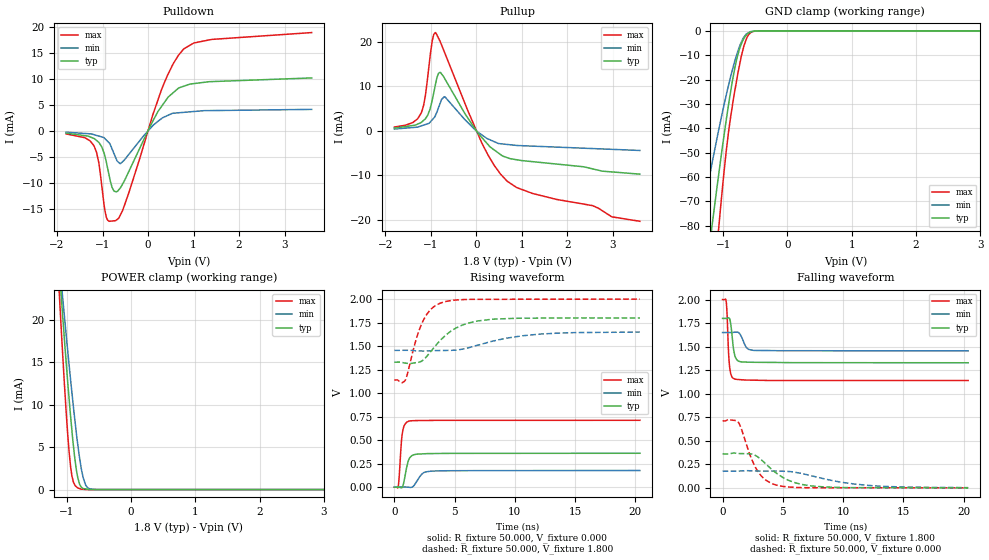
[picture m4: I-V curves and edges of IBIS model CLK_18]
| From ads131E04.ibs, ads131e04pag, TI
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|   CLK 1.8V Model
[Model]   CLK_18
Model_type   I/O
|for ADS1291, ADS1292, ADS1294, ADS1296, and ADS1298 products
|Signals   CLK
Vinl = 0.36
Vinh = 1.44
Vmeas = 0.9
Vref = 0.9
Cref = 2pF
Rref = 50
|   typ   min   max
|   (nom PVT)   (Fast PVT)   (slow PVT)
|C_comp from frequency sweep method (F=64MHz)
|   (HIGH Z)
|C_comp   3.3925780e-12   2.5074750e-12   4.1770800e-12
|   (ON state)
|C_comp   6.2108590e-12   5.2318900e-12   6.1945700e-12
|   (OFF state)
|C_comp   5.5891630e-12   4.8298730e-12   6.3388710e-12
|C_comp from LC tank measurement(L=1nH)
|   (HIGH Z)
|C_comp   2.680E-12   2.023E-12   3.327E-12
|   (ON state)
C_comp   2.729E-12   2.099E-12   3.405E-12
|   (OFF state)
|C_comp   2.780E-12   2.129E-12   3.420E-12
| Where   nom PVT is  Nominal Process, 1.8V, 27C
|   Fast PVT is Strong Process, 2V, -40C
|   Slow PVT is Weak Process, 1.65V, 85C
[Voltage Range]   1.8   1.65   2
[Temperature Range]   27   85   -40
[Pullup Reference]   1.8   1.65   2
[Pulldown Reference]   0   0   0
[Power Clamp Reference]   1.8   1.65   2
[GND Clamp Reference]   0   0   0
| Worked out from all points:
|   slope of the pulldown table from 0 to 0.27 V, typ, clamps not added: 62.3 ohm
|   slope of the pullup table from 0 to 0.27 V, typ, clamps not added: 82.7 ohm
|   GND clamp passes 1 mA (typ) near -0.61 V on its own axis
|   POWER clamp passes 1 mA (typ) near -0.81 V on its own axis
|   falling waveform, R_fixture 50.000, V_fixture 1.800: 20-80 % time 269ps typ, 419ps min, 188ps max; typ from 1.8 V to 1.33 V
|   rising waveform, R_fixture 50.000, V_fixture 0.000: 20-80 % time 368ps typ, 577ps min, 242ps max; typ from 0 V to 0.361 V
|   rising waveform, R_fixture 50.000, V_fixture 1.800: 20-80 % time 2.43ns typ, 4.23ns min, 1.35ns max; typ from 1.33 V to 1.8 V
|   falling waveform, R_fixture 50.000, V_fixture 0.000: 20-80 % time 2.34ns typ, 4.25ns min, 1.4ns max; typ from 0.361 V to 0 V
[Pulldown]
|   Voltage   I(typ)   I(min)   I(max)
-1.8V     -493.2uA   -302.1uA   -631.4uA
-1.191V   -1.505mA   -775.3uA   -2.881mA
-1.084V   -2.234mA   -1.045mA   -6.051mA
-918.3mV  -5.961mA   -1.79mA    -16.6mA
-791.5mV  -10.9mA    -3.51mA    -17.41mA
-714.1mV  -11.75mA   -5.143mA   -17.34mA
-599.3mV  -10.92mA   -6.311mA   -16.09mA
311.8mV   4.85mA     2.433mA    8.245mA
556.7mV   7.331mA    3.351mA    12.94mA
782.1mV   8.544mA    3.517mA    15.72mA
1.395V    9.438mA    3.859mA    17.56mA
3.595V    10.14mA    4.088mA    18.88mA
[GND Clamp]
|   Voltage   I(typ)   I(min)   I(max)
-1.8V     -221.5mA   -150.4mA   -312.9mA
-1.346V   -117.2mA   -78.92mA   -166mA
-1.171V   -79.66mA   -54.16mA   -111.4mA
-1.071V   -59.22mA   -40.84mA   -81.37mA
-1.048V   -54.64mA   -37.94mA   -74.6mA
-989.5mV  -43.49mA   -30.77mA   -58.64mA
-918.4mV  -30.68mA   -22.58mA   -41.92mA
-825.9mV  -16.25mA   -13.02mA   -25.67mA
-746mV    -7.45mA    -6.512mA   -14.15mA
-674.7mV  -3.047mA   -2.53mA    -5.952mA
-571.9mV  -449.7uA   -310.7uA   -783.2uA
3.595V    0A         0A         0A
[Pullup]
|   Voltage   I(typ)   I(min)   I(max)
-1.8V     604.7uA    404.2uA    846.7uA
-1.396V   1.195mA    743.5uA    1.856mA
-1.209V   1.89mA     1.114mA    4.009mA
-1.121V   2.66mA     1.413mA    7.716mA
-1.019V   4.768mA    1.896mA    16.28mA
-964.3mV  7.072mA    2.522mA    20.37mA
-899.1mV  10.29mA    3.431mA    22.08mA
-796.1mV  13.13mA    6.14mA     20.14mA
-688.4mV  11.64mA    7.634mA    17.4mA
123.9mV   -1.528mA   -935.7uA   -2.78mA
667.9mV   -5.984mA   -3.047mA   -11.2mA
3.595V    -9.731mA   -4.412mA   -20.33mA
[POWER Clamp]
|   Voltage   I(typ)   I(min)   I(max)
-1.8V     105.8mA    89.96mA    127.6mA
-1.113V   25.88mA    26.81mA    22.85mA
-1.076V   21.9mA     23.73mA    17.78mA
-1.062V   20.36mA    22.51mA    15.82mA
-1.009V   15.06mA    18.29mA    9.223mA
-959.2mV  10.4mA     14.44mA    4.184mA
-935.9mV  8.356mA    12.66mA    2.499mA
-896mV    5.198mA    9.77mA     901.6uA
-825.9mV  1.35mA     5.197mA    188.8uA
-743.6mV  126uA      1.39mA     36.03uA
-649.3mV  11.16uA    106.7uA    6.529uA
3.595V    0A         0A         0A
[Ramp]
R_load = 50
|   typ   min   max
dV/dt_r   0.216436/3.65589e-010  0.106791/5.67116e-010  0.426817/2.41454e-010
dV/dt_f   0.282366/2.66854e-010  0.116758/4.12675e-010  0.515704/1.86981e-010
[Falling Waveform]
R_fixture = 50.000
V_fixture = 1.800
V_fixture_min = 1.650
V_fixture_max = 2.000
C_fixture = 0.000
|  time   V(typ)   V(min)   V(max)
0s        1.8V       1.65V      2V
292.9ps   1.8V       1.65V      1.988V
370.7ps   1.802V     1.65V      1.847V
497.6ps   1.806V     1.65V      1.434V
583.4ps   1.796V     1.65V      1.288V
995.4ps   1.416V     1.653V     1.156V
1.306ns   1.347V     1.652V     1.151V
1.996ns   1.336V     1.488V     1.145V
2.58ns    1.334V     1.46V      1.144V
20.38ns   1.329V     1.455V     1.14V
[Rising Waveform]
R_fixture = 50.000
V_fixture = 0.000
V_fixture_min = 0.000
V_fixture_max = 0.000
C_fixture = 0.000
|  time   V(typ)   V(min)   V(max)
0s        -431.4nV   2.268mV    -804.2nV
331.8ps   193.7uV    2.309mV    13.72mV
409ps     -442.6uV   2.318mV    125.3mV
592.7ps   -6.331mV   2.34mV     491mV
719.1ps   18.89mV    2.356mV    612.2mV
1.203ns   294.8mV    -967uV     702.5mV
1.543ns   340.6mV    5.72mV     707mV
2.355ns   354.5mV    147.2mV    709.1mV
3.046ns   357.6mV    170.7mV    710mV
20.38ns   360.7mV    177.2mV    711.4mV
[Rising Waveform]
R_fixture = 50.000
V_fixture = 1.800
V_fixture_min = 1.650
V_fixture_max = 2.000
C_fixture = 0.000
|  time   V(typ)   V(min)   V(max)
0s        1.329V     1.455V     1.14V
897.3ps   1.32V      1.456V     1.135V
1.83ns    1.325V     1.45V      1.581V
2.395ns   1.352V     1.448V     1.772V
3.101ns   1.455V     1.451V     1.9V
4.073ns   1.594V     1.454V     1.969V
5.704ns   1.727V     1.469V     1.995V
8.194ns   1.787V     1.554V     1.998V
12.17ns   1.799V     1.629V     1.999V
20.38ns   1.8V       1.65V      2V
[Falling Waveform]
R_fixture = 50.000
V_fixture = 0.000
V_fixture_min = 0.000
V_fixture_max = 0.000
C_fixture = 0.000
|  time   V(typ)   V(min)   V(max)
0s        360.7mV    177.2mV    711.4mV
1.289ns   365.9mV    177.9mV    699.3mV
2.339ns   360.9mV    181.2mV    328.4mV
2.859ns   334.7mV    178.9mV    188.6mV
3.555ns   258mV      178.5mV    85.25mV
4.436ns   159.2mV    178mV      30.49mV
6.096ns   51.62mV    163.3mV    4.507mV
8.551ns   8.727mV    92.22mV    1.565mV
12.72ns   1.932mV    20.53mV    1.013mV
20.38ns   -431.4nV   2.268mV    -804.2nV
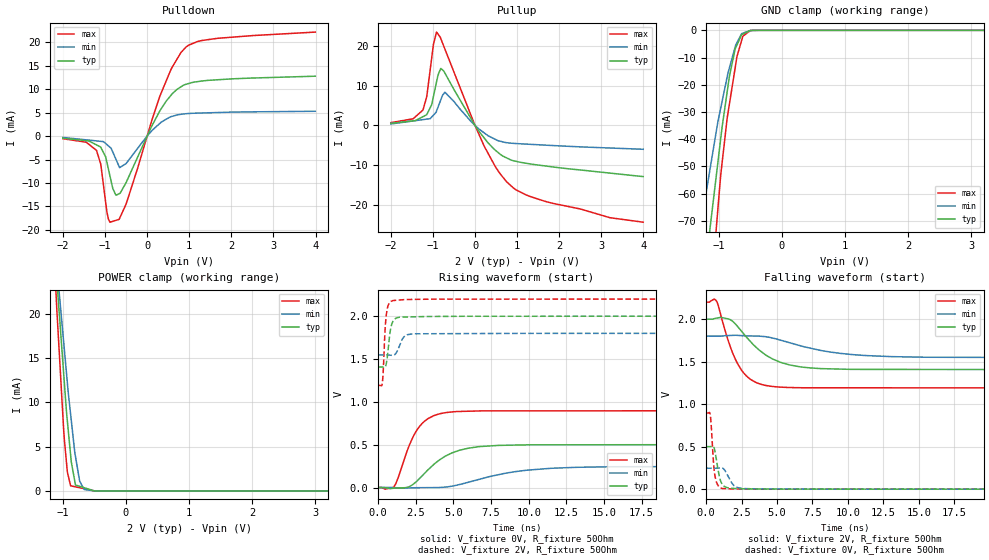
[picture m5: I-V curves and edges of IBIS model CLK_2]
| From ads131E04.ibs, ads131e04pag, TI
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|   CLK 2.0V Model
[Model]   CLK_2
Model_type   I/O
|for ADS1299 products
|Signals   CLK
Vinl = 0.4
Vinh = 1.6
Vmeas = 1.0
Vref = 1.0
Cref = 2pF
Rref = 50
|   typ   min   max
|   (nom PVT)   (Fast PVT)   (slow PVT)
|C_comp from LC tank measurement(L=1nH)
|   (HIGH Z)
|C_comp   2.643E-12   1.996E-12   3.327E-12
|   (ON state)
C_comp   2.680E-12   2.080E-12   3.358E-12
|   (OFF state)
|C_comp   2.720E-12   2.184E-12   3.389E-12
| Where   nom PVT is  Nominal Process, 2V, 27C
|   Fast PVT is Strong Process, 2.2V, -40C
|   Slow PVT is Weak Process, 1.8V, 85C
[Voltage Range]   2   1.8   2.2
[Temperature Range]   27   85   -40
[Pullup Reference]   2   1.8   2.2
[Pulldown Reference]   0   0   0
[Power Clamp Reference]   2   1.8   2.2
[GND Clamp Reference]   0   0   0
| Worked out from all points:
|   slope of the pulldown table from 0 to 0.3 V, typ, clamps not added: 56 ohm
|   slope of the pullup table from 0 to 0.3 V, typ, clamps not added: 70.1 ohm
|   GND clamp passes 1 mA (typ) near -0.58 V on its own axis
|   POWER clamp passes 1 mA (typ) near -0.81 V on its own axis
|   falling waveform, V_fixture 2V, R_fixture 50Ohm: 20-80 % time 2.39ns typ, 4.11ns min, 1.41ns max; typ from 2 V to 1.41 V
|   rising waveform, V_fixture 0V, R_fixture 50Ohm: 20-80 % time 2.14ns typ, 3.9ns min, 1.31ns max; typ from 0 V to 0.501 V
|   rising waveform, V_fixture 2V, R_fixture 50Ohm: 20-80 % time 259ps typ, 388ps min, 183ps max; typ from 1.41 V to 2 V
|   falling waveform, V_fixture 0V, R_fixture 50Ohm: 20-80 % time 342ps typ, 520ps min, 232ps max; typ from 0.501 V to 0 V
[Pulldown]
|   Voltage   I(typ)   I(min)   I(max)
-2V       -446.8uA   -277.7uA   -546.8uA
-1.203V   -1.857mA   -1.015mA   -3.03mA
-1.098V   -2.444mA   -1.112mA   -6.179mA
-920.4mV  -6.972mA   -2.066mA   -17.65mA
-815.9mV  -11.15mA   -3.375mA   -18.18mA
-664.4mV  -12.28mA   -6.492mA   -17.75mA
-499mV    -9.914mA   -5.85mA    -14.5mA
303.4mV   5.413mA    2.729mA    8.536mA
591.2mV   8.984mA    4.218mA    14.65mA
921.7mV   11.06mA    4.783mA    18.99mA
1.667V    12.03mA    5.035mA    20.87mA
3.994V    12.79mA    5.303mA    22.2mA
[GND Clamp]
|   Voltage   I(typ)   I(min)   I(max)
-2V       -269mA     -184.2mA   -378.3mA
-1.285V   -104.2mA   -71.46mA   -146.6mA
-1.134V   -72.01mA   -50.49mA   -100.5mA
-1.098V   -64.89mA   -45.37mA   -89.18mA
-1.016V   -48.91mA   -33.89mA   -66.25mA
-965.6mV  -39.22mA   -28.24mA   -52.59mA
-866.6mV  -22.65mA   -17.13mA   -32.32mA
-830.5mV  -16.83mA   -13.77mA   -27.05mA
-712.4mV  -5.47mA    -4.604mA   -9.832mA
-635.3mV  -1.567mA   -1.183mA   -3.571mA
-452.8mV  -47.95uA   -18.58uA   -21.29uA
3.994V    0A         0A         0A
[Pullup]
|   Voltage   I(typ)   I(min)   I(max)
-2V       546.5uA    370.9uA    725.3uA
-1.473V   1.156mA    1.134mA    1.672mA
-1.239V   2.209mA    1.472mA    3.871mA
-1.145V   2.784mA    1.608mA    7.428mA
-1.03V    5.235mA    2.119mA    16.97mA
-914.3mV  10.99mA    3.649mA    23.59mA
-815.9mV  14.36mA    6.395mA    22.02mA
-715.6mV  13.25mA    8.39mA     19.3mA
212.3mV   -3.088mA   -1.835mA   -5.114mA
752.4mV   -8.207mA   -4.357mA   -14.26mA
1.667V    -10.23mA   -4.968mA   -19.18mA
3.994V    -12.92mA   -6.02mA    -24.44mA
[POWER Clamp]
|   Voltage   I(typ)   I(min)   I(max)
-2V       129.9mA    109.1mA    159.1mA
-1.268V   43.13mA    40.31mA    45.46mA
-1.098V   24.26mA    25.49mA    20.67mA
-1.077V   21.92mA    23.81mA    18.02mA
-978.5mV  12.38mA    16.1mA     5.95mA
-929.4mV  7.886mA    12.23mA    2.13mA
-877.6mV  4.05mA     8.652mA    577.2uA
-800.7mV  668.9uA    3.894mA    460uA
-736.6mV  526.2uA    1.192mA    362.2uA
-663.7mV  363.8uA    165.5uA    251uA
-500.2mV  55.26nA    1.607uA    1.869uA
3.994V    0A         0A         0A
[Ramp]
R_load = 50
|   typ   min   max
dV/dt_r   0.300353/2.13181e-009  0.147667/3.87445e-009  0.537699/1.30968e-009
dV/dt_f   0.356044/2.37906e-009  0.151292/4.09808e-009  0.605232/1.41362e-009
[Falling Waveform]
V_fixture = 2V
V_fixture_min = 1.8V
V_fixture_max = 2.2V
R_fixture = 50Ohm
C_fixture = 0F
|   Time   V(typ)   V(min)   V(max)
0s        2V         1.8V       2.2V
753.9ps   2.013V     1.8V       2.208V
1.711ns   1.993V     1.808V     1.673V
2.468ns   1.864V     1.806V     1.408V
3.126ns   1.737V     1.802V     1.292V
4.015ns   1.602V     1.797V     1.227V
5.887ns   1.461V     1.723V     1.196V
8.107ns   1.418V     1.631V     1.193V
13.07ns   1.409V     1.559V     1.192V
25ns      1.407V     1.548V     1.191V
[Rising Waveform]
V_fixture = 0V
V_fixture_min = 0V
V_fixture_max = 0V
R_fixture = 50Ohm
C_fixture = 0F
|   Time   V(typ)   V(min)   V(max)
0s        183.8nV    7.808uV    2.991nV
1.044ns   -8.034mV   -775.9uV   10.05mV
1.314ns   -4.793mV   -3.416mV   108mV
2.073ns   11.03mV    -4.509mV   495.9mV
2.579ns   75.85mV    -2.162mV   672.2mV
3.281ns   201.5mV    -1.317mV   801.1mV
4.203ns   337.4mV    2.169mV    865.5mV
6.599ns   475mV      90.46mV    893.5mV
11.42ns   498.8mV    223.9mV    895.2mV
25ns      500.6mV    246.1mV    896.2mV
[Rising Waveform]
V_fixture = 2V
V_fixture_min = 1.8V
V_fixture_max = 2.2V
R_fixture = 50Ohm
C_fixture = 0F
|   Time   V(typ)   V(min)   V(max)
0s        1.407V     1.548V     1.191V
280.5ps   1.406V     1.548V     1.229V
342.2ps   1.404V     1.548V     1.385V
465.1ps   1.407V     1.548V     1.865V
581.3ps   1.491V     1.548V     2.068V
794.8ps   1.819V     1.545V     2.165V
985.6ps   1.941V     1.544V     2.183V
1.706ns   1.99V      1.758V     2.193V
2.305ns   1.992V     1.794V     2.196V
25ns      2V         1.8V       2.2V
[Falling Waveform]
|Gnd
V_fixture = 0V
V_fixture_min = 0V
V_fixture_max = 0V
R_fixture = 50Ohm
C_fixture = 0F
|   Time   V(typ)   V(min)   V(max)
0s        500.6mV    246.1mV    896.2mV
293.6ps   500.4mV    246.1mV    873.2mV
361.8ps   502.7mV    246.1mV    743.5mV
533.6ps   497.5mV    246mV      287mV
653.3ps   420.1mV    246mV      130.7mV
920.4ps   158.6mV    249.3mV    27.36mV
1.103ns   67.19mV    250mV      9.48mV
1.968ns   8.479mV    41.8mV     2.924mV
2.739ns   3.643mV    7.088mV    1.938mV
25ns      189.2nV    8.004uV    64.84nV
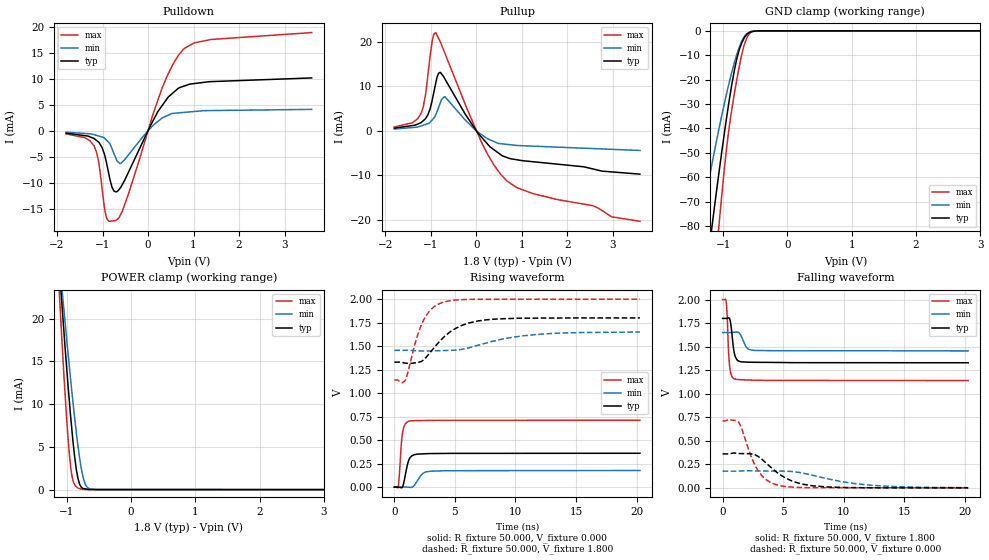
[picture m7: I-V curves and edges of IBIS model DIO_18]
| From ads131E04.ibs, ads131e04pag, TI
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|   DIO 1.8V Model
[Model]   DIO_18
Model_type   I/O
|for ADS1291, ADS1292, ADS1294, ADS1296, and ADS1298 products
|Signals   SCLK, DAISY_IN
Vinl = .36
Vinh = 1.44
Vmeas = 0.9
Vref = 0.9
Cref = 2pF
Rref = 50
|   typ   min   max
|   (nom PVT)   (Fast PVT)   (slow PVT)
|C_comp from frequency sweep method (F=64MHz)
|   (HIGH Z)
|C_comp   3.4090070e-12   2.5132430e-12   4.2130700e-12
|   (ON state)
|C_comp   6.2272870e-12   5.2376580e-12   6.2305600e-12
|   (OFF state)
|C_comp   5.6001660e-12   4.8341510e-12   6.3523670e-12
|C_comp from LC tank measurement(L=1nH)
|   (HIGH Z)
|C_comp   2.692E-12   2.052E-12   3.343E-12
|   (ON state)
C_comp   2.680E-12   2.052E-12   3.343E-12
|   (OFF state)
|C_comp   2.793E-12   2.148E-12   3.318E-12
| Where   nom PVT is  Nominal Process, 1.8V, 27C
|   Fast PVT is Strong Process, 2V, -40C
|   Slow PVT is Weak Process, 1.65V, 85C
[Voltage Range]   1.8   1.65   2
[Temperature Range]   27   85   -40
[Pullup Reference]   1.8   1.65   2
[Pulldown Reference]   0   0   0
[Power Clamp Reference]   1.8   1.65   2
[GND Clamp Reference]   0   0   0
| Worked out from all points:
|   slope of the pulldown table from 0 to 0.27 V, typ, clamps not added: 62.3 ohm
|   slope of the pullup table from 0 to 0.27 V, typ, clamps not added: 82.6 ohm
|   GND clamp passes 1 mA (typ) near -0.61 V on its own axis
|   POWER clamp passes 1 mA (typ) near -0.81 V on its own axis
|   falling waveform, R_fixture 50.000, V_fixture 1.800: 20-80 % time 273ps typ, 421ps min, 190ps max; typ from 1.8 V to 1.33 V
|   rising waveform, R_fixture 50.000, V_fixture 0.000: 20-80 % time 375ps typ, 589ps min, 246ps max; typ from 0 V to 0.361 V
|   rising waveform, R_fixture 50.000, V_fixture 1.800: 20-80 % time 2.44ns typ, 4.26ns min, 1.35ns max; typ from 1.33 V to 1.8 V
|   falling waveform, R_fixture 50.000, V_fixture 0.000: 20-80 % time 2.39ns typ, 4.39ns min, 1.43ns max; typ from 0.361 V to 0 V
[Pulldown]
|   Voltage   I(typ)   I(min)   I(max)
-1.8V     -493.2uA   -302.1uA   -631.4uA
-1.191V   -1.504mA   -776.7uA   -2.888mA
-1.088V   -2.209mA   -1.036mA   -5.858mA
-918.2mV  -5.97mA    -1.787mA   -16.6mA
-791.5mV  -10.9mA    -3.51mA    -17.41mA
-713.9mV  -11.76mA   -5.147mA   -17.34mA
-597.1mV  -10.88mA   -6.302mA   -16.05mA
305mV     4.764mA    2.381mA    8.093mA
548.6mV   7.268mA    3.324mA    12.81mA
785.1mV   8.557mA    3.504mA    15.74mA
1.391V    9.437mA    3.861mA    17.55mA
3.595V    10.14mA    4.088mA    18.88mA
[GND Clamp]
|   Voltage   I(typ)   I(min)   I(max)
-1.8V     -221.5mA   -150.4mA   -312.9mA
-1.345V   -116.9mA   -78.75mA   -165.7mA
-1.173V   -79.95mA   -54.35mA   -111.8mA
-1.066V   -58.37mA   -40.28mA   -80.1mA
-952.5mV  -36.68mA   -26.42mA   -49.43mA
-880.8mV  -24.43mA   -18.46mA   -34.77mA
-818mV    -15.15mA   -12.29mA   -24.49mA
-749.1mV  -7.708mA   -6.74mA    -14.56mA
-638.6mV  -1.69mA    -1.264mA   -3.326mA
-563.3mV  -385.1uA   -280.7uA   -585uA
-450.7mV  -21.72uA   -40.51uA   -19.25uA
3.595V    0A         0A         0A
[Pullup]
|   Voltage   I(typ)   I(min)   I(max)
-1.8V     604.7uA    404.2uA    846.7uA
-1.402V   1.188mA    738.6uA    1.825mA
-1.212V   1.854mA    1.106mA    3.943mA
-1.121V   2.67mA     1.418mA    7.738mA
-1.021V   4.713mA    1.866mA    16.14mA
-964mV    7.077mA    2.51mA     20.38mA
-898.8mV  10.29mA    3.441mA    22.08mA
-796.1mV  13.13mA    6.135mA    20.14mA
-688.4mV  11.64mA    7.634mA    17.4mA
125.5mV   -1.548mA   -927.7uA   -2.813mA
666.9mV   -5.975mA   -3.039mA   -11.2mA
3.595V    -9.731mA   -4.412mA   -20.33mA
[POWER Clamp]
|   Voltage   I(typ)   I(min)   I(max)
-1.8V     105.8mA    89.96mA    127.6mA
-1.113V   25.84mA    26.78mA    22.81mA
-1.075V   21.71mA    23.58mA    17.54mA
-1.061V   20.35mA    22.5mA     15.8mA
-1.009V   15.02mA    18.26mA    9.187mA
-959mV    10.37mA    14.42mA    4.163mA
-935.7mV  8.337mA    12.64mA    2.485mA
-895.7mV  5.18mA     9.749mA    895.8uA
-825.5mV  1.34mA     5.18mA     187.3uA
-741.4mV  123.4uA    1.327mA    34.5uA
-653.5mV  16.35uA    121.6uA    6.493uA
3.595V    0A         0A         0A
[Ramp]
R_load = 50
|   typ   min   max
dV/dt_r   0.216438/3.71476e-010  0.106792/5.78707e-010  0.426816/2.45154e-010
dV/dt_f   0.282368/2.69166e-010  0.116759/4.14702e-010  0.515701/1.89304e-010
[Falling Waveform]
R_fixture = 50.000
V_fixture = 1.800
V_fixture_min = 1.650
V_fixture_max = 2.000
C_fixture = 0.000
|  time   V(typ)   V(min)   V(max)
0s        1.8V       1.65V      2V
292.9ps   1.8V       1.65V      1.988V
370.9ps   1.802V     1.65V      1.847V
497.9ps   1.806V     1.65V      1.437V
589.1ps   1.794V     1.65V      1.285V
1.001ns   1.415V     1.653V     1.156V
1.313ns   1.347V     1.651V     1.151V
2.005ns   1.336V     1.487V     1.145V
2.589ns   1.334V     1.46V      1.144V
20.28ns   1.329V     1.455V     1.14V
[Rising Waveform]
R_fixture = 50.000
V_fixture = 0.000
V_fixture_min = 0.000
V_fixture_max = 0.000
C_fixture = 0.000
|  time   V(typ)   V(min)   V(max)
0s        -441.2nV   2.228mV    817.7nV
331.8ps   189.6uV    2.268mV    13.39mV
409.2ps   -437.8uV   2.277mV    123.2mV
594.9ps   -6.273mV   2.3mV      488.6mV
723.1ps   20.01mV    2.315mV    610.8mV
1.209ns   293.8mV    -987uV     702.4mV
1.545ns   339.7mV    5.538mV    707mV
2.378ns   354.5mV    147.5mV    709.1mV
3.063ns   357.6mV    170.6mV    710.1mV
20.28ns   360.7mV    177.2mV    711.4mV
[Rising Waveform]
R_fixture = 50.000
V_fixture = 1.800
V_fixture_min = 1.650
V_fixture_max = 2.000
C_fixture = 0.000
|  time   V(typ)   V(min)   V(max)
0s        1.329V     1.455V     1.14V
898.6ps   1.32V      1.456V     1.135V
1.859ns   1.325V     1.45V      1.592V
2.377ns   1.35V      1.448V     1.767V
3.049ns   1.447V     1.449V     1.893V
3.984ns   1.583V     1.453V     1.965V
5.582ns   1.721V     1.466V     1.994V
7.589ns   1.78V      1.533V     1.998V
11.99ns   1.798V     1.627V     1.999V
20.28ns   1.8V       1.65V      2V
[Falling Waveform]
R_fixture = 50.000
V_fixture = 0.000
V_fixture_min = 0.000
V_fixture_max = 0.000
C_fixture = 0.000
|  time   V(typ)   V(min)   V(max)
0s        360.7mV    177.2mV    711.4mV
1.309ns   365.7mV    178mV      699.4mV
2.405ns   359.7mV    180.8mV    318.9mV
2.893ns   337.3mV    178.9mV    190.6mV
3.61ns    261.7mV    178.5mV    85.03mV
4.494ns   163.7mV    178.2mV    30.72mV
6.148ns   54.99mV    166.9mV    4.658mV
8.586ns   9.739mV    98.9mV     1.486mV
13.38ns   452.6uV    18.33mV    876.9uV
20.28ns   -441.2nV   2.228mV    817.7nV
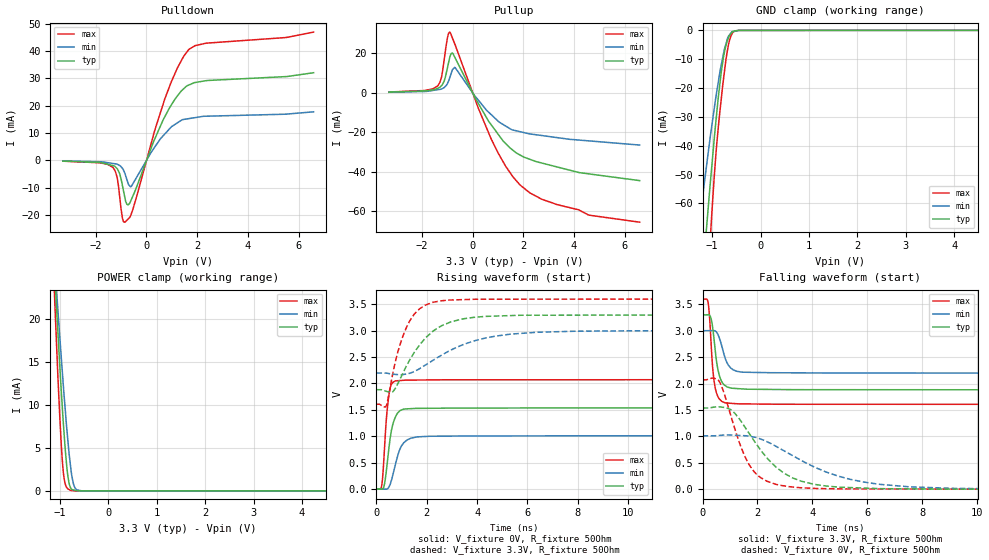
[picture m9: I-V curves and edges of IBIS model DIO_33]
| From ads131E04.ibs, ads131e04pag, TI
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|   DIO 3.3V  Model
[Model]   DIO_33
Model_type   I/O
|for all products
|Signals   SCLK, DAISY_IN
Vinl = 0.66
Vinh = 2.64
Vmeas = 1.65
Vref = 1.65
Cref = 2pF
Rref = 50
|   typ   min   max
|   (nom PVT)   (Fast PVT)   (slow PVT)
|C_comp from frequency sweep method (F=64MHz)
|   (Hight Z)
|C_comp   3.0727220e-12   2.3187130e-12   3.8529520e-12
|   (ON state)
|C_comp   5.2856500e-12   4.3183460e-12   6.0694320e-12
|   (OFF state)
|C_comp   6.2160260e-12   5.1916700e-12   7.4675830e-12
|C_comp from LC tank measurement(L=1nH)
|   (HIGH Z)
|C_comp   2.684E-12   1.884E-12   3.034E-12
|   (ON state)
C_comp   2.680E-12   1.915E-12   3.021E-12
|   (OFF state)
|C_comp   2.777E-12   2.090E-12   3.207E-12
| Where   nom PVT is  Nominal Process, 3.3V, 27C
|   Fast PVT is Strong Process, 3.6V, -40C
|   Slow PVT is Weak Process, 3V, 85C
[Voltage Range]   3.3   3   3.6
[Temperature Range]   27   85   -40
[Pullup Reference]   3.3   3   3.6
[Pulldown Reference]   0   0   0
[Power Clamp Reference]   3.3   3   3.6
[GND Clamp Reference]   0   0   0
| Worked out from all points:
|   slope of the pulldown table from 0 to 0.495 V, typ, clamps not added: 43.2 ohm
|   slope of the pullup table from 0 to 0.495 V, typ, clamps not added: 43.3 ohm
|   GND clamp passes 1 mA (typ) near -0.61 V on its own axis
|   POWER clamp passes 1 mA (typ) near -0.81 V on its own axis
|   falling waveform, V_fixture 3.3V, R_fixture 50Ohm: 20-80 % time 225ps typ, 301ps min, 171ps max; typ from 3.3 V to 1.88 V
|   rising waveform, V_fixture 0V, R_fixture 50Ohm: 20-80 % time 269ps typ, 367ps min, 188ps max; typ from 0 V to 1.54 V
|   rising waveform, V_fixture 3.3V, R_fixture 50Ohm: 20-80 % time 1.3ns typ, 2.17ns min, 767ps max; typ from 1.88 V to 3.3 V
|   falling waveform, V_fixture 0V, R_fixture 50Ohm: 20-80 % time 1.48ns typ, 2.57ns min, 883ps max; typ from 1.54 V to 0 V
[Pulldown]
|   Voltage   I(typ)   I(min)   I(max)
-3.3V     -285.2uA   -205.1uA   -305.9uA
-1.331V   -1.918mA   -1.131mA   -2.55mA
-1.167V   -2.954mA   -1.36mA    -5.856mA
-1.063V   -4.742mA   -1.873mA   -12.85mA
-947.9mV  -9.251mA   -2.925mA   -21.16mA
-848mV    -13.81mA   -4.854mA   -22.6mA
-724.8mV  -16.24mA   -8.384mA   -21.46mA
-603.5mV  -14.46mA   -9.523mA   -19.64mA
712.1mV   15.75mA    9.525mA    22.14mA
1.213V    23.46mA    13.66mA    33.62mA
1.658V    27.47mA    15.22mA    40.4mA
6.59V     32.02mA    17.73mA    46.86mA
[GND Clamp]
|   Voltage   I(typ)   I(min)   I(max)
-3.3V     -585.9mA   -419.8mA   -805.2mA
-1.268V   -100.1mA   -67.65mA   -141.3mA
-1.129V   -71.04mA   -48.6mA    -98.59mA
-1.068V   -58.75mA   -40.62mA   -80.55mA
-1.033V   -51.79mA   -36.04mA   -70.56mA
-1.01V    -47.53mA   -33.36mA   -64.21mA
-905.6mV  -28.59mA   -21.26mA   -39.39mA
-811.8mV  -14.36mA   -11.92mA   -23.66mA
-695.6mV  -4.024mA   -3.572mA   -7.988mA
-590.4mV  -636uA     -463.2uA   -1.221mA
-452.4mV  -20.71uA   -46.86uA   -20.53uA
6.59V     0A         0A         0A
[Pullup]
|   Voltage   I(typ)   I(min)   I(max)
-3.3V     365.8uA    284.3uA    421.3uA
-1.388V   2.254mA    1.561mA    3.388mA
-1.228V   3.629mA    1.902mA    7.896mA
-1.121V   5.948mA    2.679mA    16.78mA
-993.8mV  12.54mA    4.697mA    27.75mA
-905.6mV  17.68mA    7.542mA    30.74mA
-804.4mV  20.17mA    11.38mA    28mA
-680.2mV  17.43mA    12.63mA    23.98mA
712.1mV   -15.78mA   -10.75mA   -22.71mA
1.867V    -31.42mA   -19.63mA   -46.55mA
4.577V    -40.98mA   -24.29mA   -61.84mA
6.59V     -44.4mA    -26.41mA   -65.43mA
[POWER Clamp]
|   Voltage   I(typ)   I(min)   I(max)
-3.3V     287.9mA    235.1mA    365.7mA
-1.126V   27.24mA    27.9mA     24.69mA
-1.109V   25.44mA    26.44mA    22.27mA
-1.055V   19.67mA    22.02mA    14.94mA
-976.5mV  11.98mA    15.8mA     5.748mA
-941.2mV  8.799mA    13.08mA    2.832mA
-905.6mV  5.954mA    10.48mA    1.155mA
-857.9mV  2.752mA    7.192mA    393.2uA
-779.8mV  358uA      2.818mA    63.69uA
-702.7mV  94.16uA    510.4uA    10.59uA
-542.5mV  4.786uA    3.781uA    5.632uA
6.59V     0A         0A         0A
[Ramp]
R_load = 50
|   typ   min   max
dV/dt_r   0.92223/2.68466e-010  0.605474/3.65952e-010   1.24254/1.87684e-010
dV/dt_f   0.851357/2.24332e-010  0.481824/3.0028e-010   1.19615/1.69977e-010
[Falling Waveform]
V_fixture = 3.3V
V_fixture_min = 3V
V_fixture_max = 3.6V
R_fixture = 50Ohm
C_fixture = 0F
|   Time   V(typ)   V(min)   V(max)
0s        3.3V       3V         3.6V
211.5ps   3.302V     3.002V     3.508V
260.2ps   3.293V     3.002V     3.226V
368ps     3.065V     3.003V     2.309V
471.6ps   2.586V     2.992V     1.896V
611.6ps   2.153V     2.863V     1.707V
820.9ps   1.963V     2.487V     1.635V
1.022ns   1.917V     2.297V     1.626V
1.453ns   1.898V     2.215V     1.615V
15.38ns   1.881V     2.197V     1.606V
[Rising Waveform]
V_fixture = 0V
V_fixture_min = 0V
V_fixture_max = 0V
R_fixture = 50Ohm
C_fixture = 0F
|   Time   V(typ)   V(min)   V(max)
0s        -1.894uV   4.058uV    2.172uV
210.3ps   -2.879mV   -2.39mV    60.6mV
330.6ps   116.2mV    -3.759mV   839.3mV
394.7ps   339.3mV    -4.488mV   1.319V
484.9ps   721.2mV    23.87mV    1.733V
589.3ps   1.091V     150.9mV    1.976V
755.5ps   1.363V     464.7mV    2.047V
1.09ns    1.514V     877.4mV    2.06V
1.612ns   1.527V     986mV      2.065V
15.38ns   1.537V     1.009V     2.071V
[Rising Waveform]
V_fixture = 3.3V
V_fixture_min = 3V
V_fixture_max = 3.6V
R_fixture = 50Ohm
C_fixture = 0F
|   Time   V(typ)   V(min)   V(max)
0s        1.881V     2.197V     1.606V
405.1ps   1.849V     2.195V     1.589V
639.5ps   1.839V     2.177V     2.159V
839.6ps   1.986V     2.169V     2.576V
1.308ns   2.432V     2.192V     3.171V
1.704ns   2.724V     2.278V     3.411V
2.229ns   2.982V     2.433V     3.536V
3.396ns   3.22V      2.727V     3.589V
5.393ns   3.288V     2.938V     3.597V
15.38ns   3.3V       3V         3.6V
[Falling Waveform]
|Gnd
V_fixture = 0V
V_fixture_min = 0V
V_fixture_max = 0V
R_fixture = 50Ohm
C_fixture = 0F
|   Time   V(typ)   V(min)   V(max)
0s        1.537V     1.009V     2.071V
599.3ps   1.559V     1.017V     2.048V
1.052ns   1.496V     1.024V     1.354V
1.407ns   1.282V     1.015V     789.6mV
1.662ns   1.084V     1.007V     496.6mV
2.08ns    767mV      956mV      231.5mV
2.66ns    423.9mV    815.2mV    93.24mV
4.034ns   95.09mV    428mV      15.67mV
6.354ns   12.09mV    97.67mV    3.661mV
15.38ns   -1.894uV   4.058uV    2.172uV
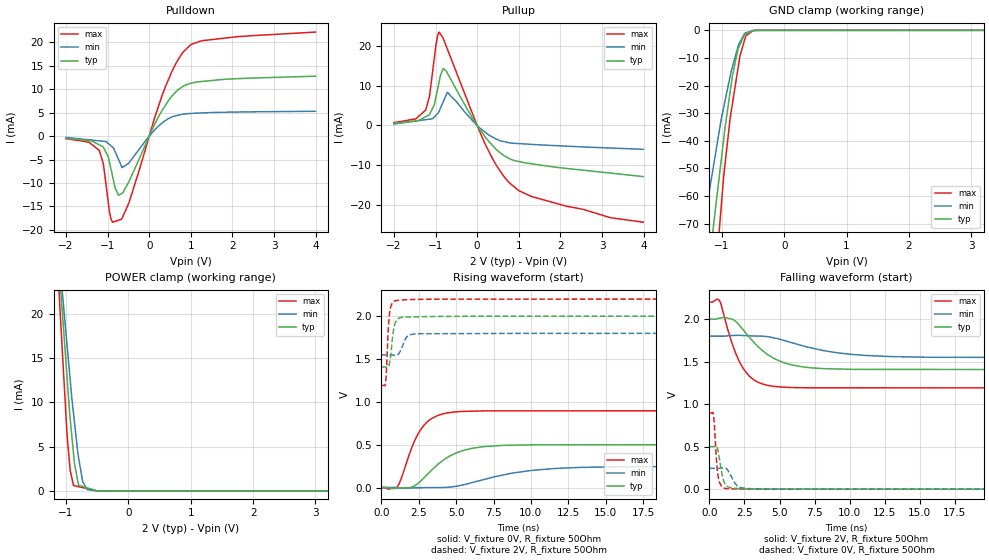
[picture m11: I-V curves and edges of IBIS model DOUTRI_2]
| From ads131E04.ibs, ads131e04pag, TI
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|   DOUTRI 2.0V Model
[Model]   DOUTRI_2
Model_type   I/O
|for ADS1299 products
|Signals   DOUT, _DRDY
Vinl = 0.4
Vinh = 1.6
Vmeas = 1
Vref = 1
Cref = 2pF
Rref = 50
|   typ   min   max
|   (nom PVT)   (Fast PVT)   (slow PVT)
|C_comp from LC tank measurement(L=1nH)
|   (HIGH Z)
|C_comp   2.542E-12   1.932E-12   3.192E-12
|   (ON state)
C_comp   2.643E-12   2.014E-12   3.251E-12
|   (OFF state)
|C_comp   2.667E-12   2.071E-12   3.297E-12
| Where   nom PVT is  Nominal Process, 2V, 27C
|   Fast PVT is Strong Process, 2.2V, -40C
|   Slow PVT is Weak Process, 1.8V, 85C
[Voltage Range]   2   1.8   2.2
[Temperature Range]   27   85   -40
[Pullup Reference]   2   1.8   2.2
[Pulldown Reference]   0   0   0
[Power Clamp Reference]   2   1.8   2.2
[GND Clamp Reference]   0   0   0
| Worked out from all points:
|   slope of the pulldown table from 0 to 0.3 V, typ, clamps not added: 55.9 ohm
|   slope of the pullup table from 0 to 0.3 V, typ, clamps not added: 70 ohm
|   GND clamp passes 1 mA (typ) near -0.59 V on its own axis
|   POWER clamp passes 1 mA (typ) near -0.81 V on its own axis
|   falling waveform, V_fixture 2V, R_fixture 50Ohm: 20-80 % time 2.39ns typ, 4.11ns min, 1.41ns max; typ from 2 V to 1.41 V
|   rising waveform, V_fixture 0V, R_fixture 50Ohm: 20-80 % time 2.19ns typ, 4.04ns min, 1.33ns max; typ from 0 V to 0.501 V
|   rising waveform, V_fixture 2V, R_fixture 50Ohm: 20-80 % time 252ps typ, 382ps min, 179ps max; typ from 1.41 V to 2 V
|   falling waveform, V_fixture 0V, R_fixture 50Ohm: 20-80 % time 338ps typ, 525ps min, 227ps max; typ from 0.501 V to 0 V
[Pulldown]
|   Voltage   I(typ)   I(min)   I(max)
-2V       -446.8uA   -277.7uA   -546.8uA
-1.45V    -956.2uA   -783.7uA   -1.281mA
-1.202V   -1.853mA   -1.012mA   -3.045mA
-1.101V   -2.408mA   -1.105mA   -6.025mA
-920.1mV  -6.984mA   -2.063mA   -17.66mA
-819.2mV  -11.04mA   -3.312mA   -18.2mA
-663.4mV  -12.27mA   -6.513mA   -17.74mA
-466.8mV  -9.289mA   -5.471mA   -13.65mA
384.5mV   6.517mA    3.282mA    10.46mA
705.2mV   9.948mA    4.471mA    16.51mA
985.7mV   11.24mA    4.83mA     19.41mA
3.994V    12.79mA    5.303mA    22.2mA
[GND Clamp]
|   Voltage   I(typ)   I(min)   I(max)
-2V       -264.7mA   -180.3mA   -373.5mA
-1.29V    -103.5mA   -70.42mA   -146.4mA
-1.133V   -70.49mA   -49.03mA   -98.82mA
-1.099V   -63.92mA   -44.33mA   -88.37mA
-1.013V   -47.59mA   -32.64mA   -64.75mA
-965.4mV  -38.46mA   -27.34mA   -51.81mA
-865.1mV  -21.99mA   -16.38mA   -31.57mA
-828.9mV  -16.29mA   -13.17mA   -26.39mA
-711.5mV  -5.284mA   -4.364mA   -9.549mA
-633.2mV  -1.497mA   -1.072mA   -3.361mA
-448.4mV  -39.89uA   -15.83uA   -17.84uA
3.994V    0A         0A         0A
[Pullup]
|   Voltage   I(typ)   I(min)   I(max)
-2V       546.5uA    370.9uA    725.3uA
-1.471V   1.156mA    1.131mA    1.681mA
-1.238V   2.209mA    1.465mA    3.888mA
-1.146V   2.757mA    1.598mA    7.345mA
-1.034V   5.114mA    2.082mA    16.66mA
-913.3mV  11.02mA    3.624mA    23.6mA
-814.3mV  14.37mA    6.016mA    21.98mA
-716.2mV  13.26mA    8.388mA    19.32mA
205.5mV   -3.046mA   -1.831mA   -4.964mA
757.5mV   -8.283mA   -4.345mA   -14.32mA
1.316V    -9.687mA   -4.778mA   -17.97mA
3.994V    -12.92mA   -6.02mA    -24.44mA
[POWER Clamp]
|   Voltage   I(typ)   I(min)   I(max)
-2V       129.9mA    109.1mA    159.1mA
-1.266V   42.87mA    40.08mA    45.12mA
-1.099V   24.37mA    25.59mA    20.8mA
-1.075V   21.8mA     23.71mA    17.89mA
-978.2mV  12.36mA    16.09mA    5.921mA
-933.3mV  8.14mA     12.57mA    2.344mA
-879.7mV  4.231mA    8.765mA    606.9uA
-864.7mV  3.129mA    7.793mA    583uA
-799.1mV  636.7uA    3.806mA    479.1uA
-734.6mV  500.8uA    1.138mA    376.9uA
-660.1mV  343.8uA    148.4uA    259uA
3.994V    0A         0A         0A
[Ramp]
R_load = 50
|   typ   min   max
dV/dt_r   0.300352/2.17638e-009  0.147657/3.99034e-009  0.537699/1.32532e-009
dV/dt_f   0.356044/2.37782e-009  0.151292/4.09711e-009  0.605232/1.41256e-009
[Falling Waveform]
V_fixture = 2V
V_fixture_min = 1.8V
V_fixture_max = 2.2V
R_fixture = 50Ohm
C_fixture = 0F
|   Time   V(typ)   V(min)   V(max)
0s        2V         1.8V       2.2V
747.5ps   2.013V     1.8V       2.21V
1.713ns   1.993V     1.808V     1.67V
2.476ns   1.861V     1.807V     1.405V
3.143ns   1.733V     1.802V     1.29V
4.053ns   1.596V     1.796V     1.225V
5.885ns   1.461V     1.723V     1.196V
8.092ns   1.418V     1.631V     1.193V
13.11ns   1.409V     1.559V     1.192V
25ns      1.407V     1.548V     1.191V
[Rising Waveform]
V_fixture = 0V
V_fixture_min = 0V
V_fixture_max = 0V
R_fixture = 50Ohm
C_fixture = 0F
|   Time   V(typ)   V(min)   V(max)
0s        184.1nV    7.792uV    2.945nV
1.058ns   -7.694mV   -917.4uV   10.22mV
1.332ns   -4.542mV   -3.587mV   108.3mV
2.102ns   9.959mV    -4.289mV   497.5mV
2.616ns   73.26mV    -2.021mV   673.8mV
3.341ns   199.8mV    -1.275mV   803.6mV
4.307ns   339.1mV    2.195mV    867.5mV
6.761ns   475.5mV    89.01mV    893.9mV
11.7ns    498.8mV    223.4mV    895.2mV
25ns      500.6mV    246.1mV    896.2mV
[Rising Waveform]
V_fixture = 2V
V_fixture_min = 1.8V
V_fixture_max = 2.2V
R_fixture = 50Ohm
C_fixture = 0F
|   Time   V(typ)   V(min)   V(max)
0s        1.407V     1.548V     1.191V
278.5ps   1.406V     1.548V     1.227V
347.9ps   1.404V     1.548V     1.41V
464.2ps   1.407V     1.548V     1.872V
576.8ps   1.487V     1.548V     2.071V
782.7ps   1.811V     1.545V     2.165V
972.5ps   1.94V      1.543V     2.183V
1.7ns     1.99V      1.759V     2.193V
2.294ns   1.992V     1.795V     2.196V
25ns      2V         1.8V       2.2V
[Falling Waveform]
|Gnd
V_fixture = 0V
V_fixture_min = 0V
V_fixture_max = 0V
R_fixture = 50Ohm
C_fixture = 0F
|   Time   V(typ)   V(min)   V(max)
0s        500.6mV    246.1mV    896.2mV
293.9ps   500.4mV    246.1mV    872.9mV
360.9ps   502.6mV    246mV      744.7mV
535.4ps   497.1mV    246mV      278.3mV
650.5ps   422.9mV    246mV      127.5mV
917.6ps   160mV      249.2mV    26.38mV
1.098ns   66.39mV    250.2mV    9.355mV
1.976ns   8.413mV    40.86mV    2.865mV
2.722ns   3.651mV    7.197mV    1.941mV
25ns      188.7nV    7.988uV    64.84nV
